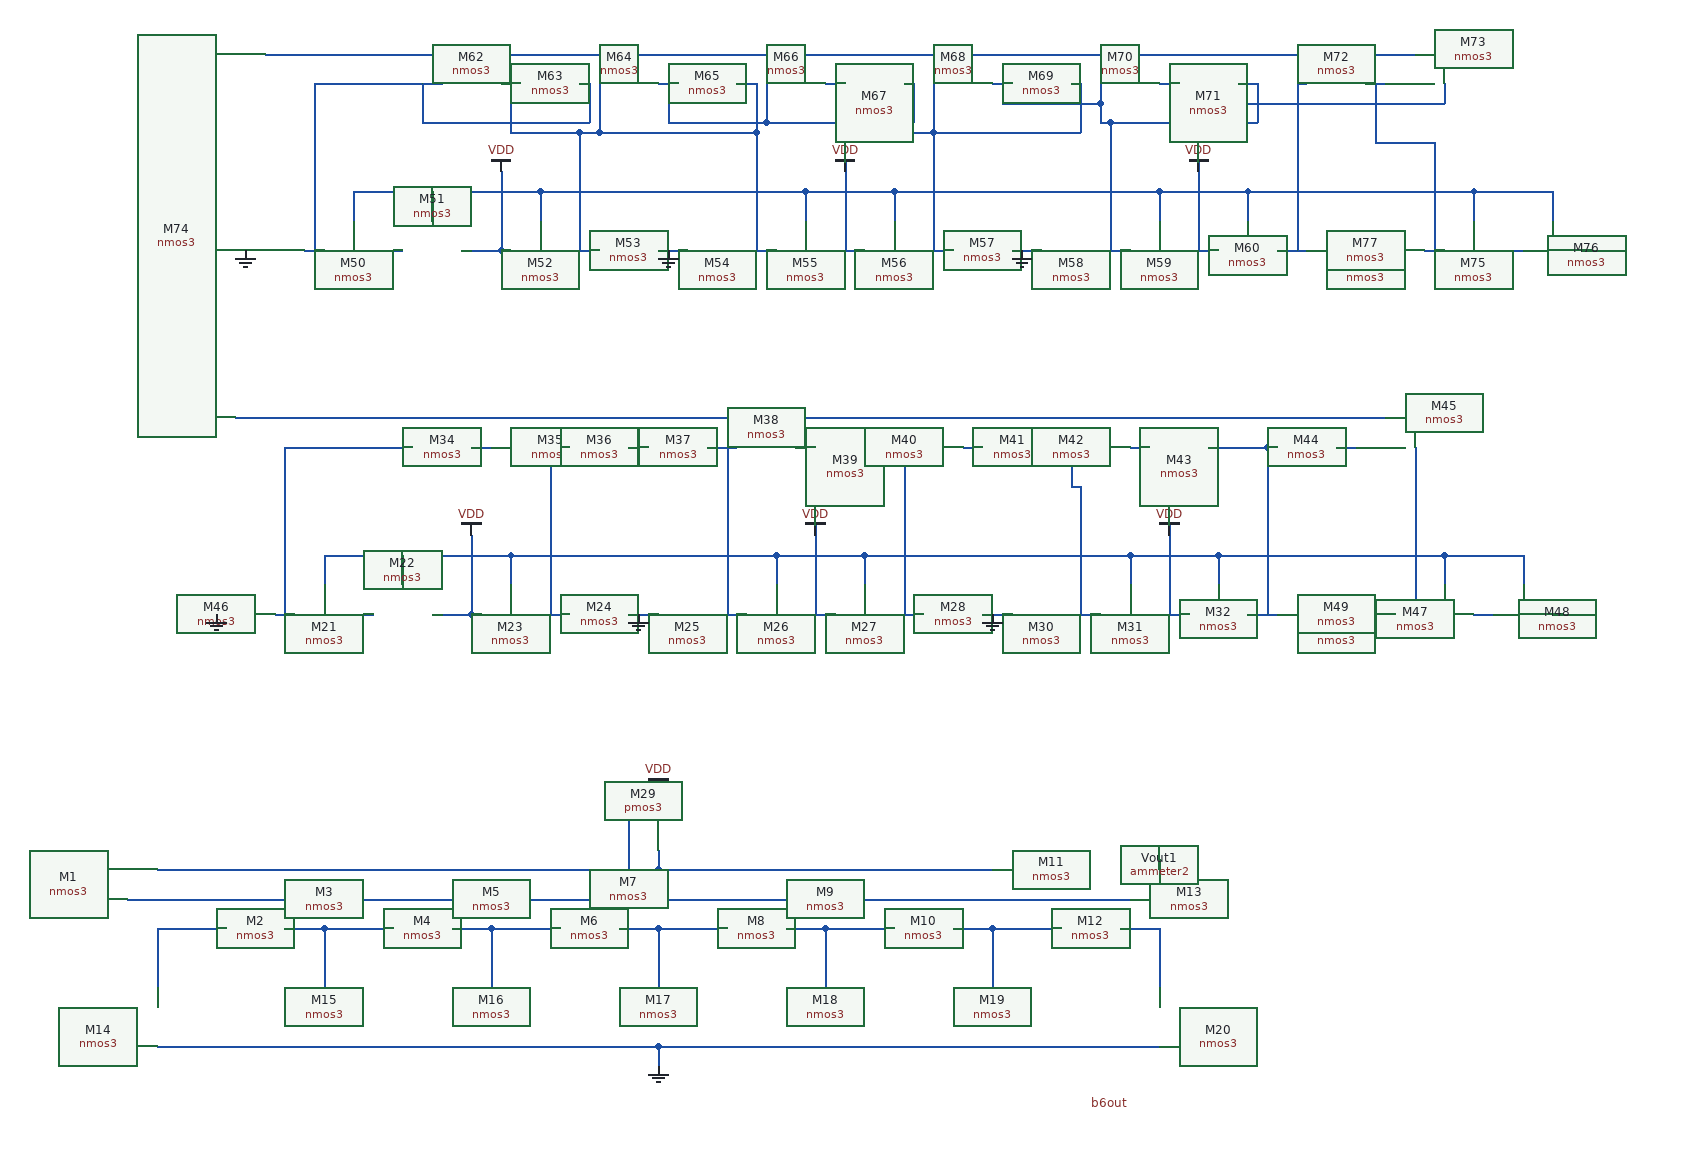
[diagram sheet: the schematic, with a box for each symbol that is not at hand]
v {xschem version=3.4.3 file_version=1.2
}
G {}
K {}
V {}
S {}
E {}
N -10 90 60 90 {
lab=#net1}
N -40 60 90 60 {
lab=#net2}
N 90 60 130 60 {
lab=#net2}
N 120 90 160 90 {
lab=#net3}
N 160 90 230 90 {
lab=#net3}
N 130 60 260 60 {
lab=#net2}
N 260 60 300 60 {
lab=#net2}
N 290 90 330 90 {
lab=#net4}
N 330 90 400 90 {
lab=#net4}
N 300 60 430 60 {
lab=#net2}
N 430 60 470 60 {
lab=#net2}
N 460 90 500 90 {
lab=#net5}
N 500 90 570 90 {
lab=#net5}
N 470 60 600 60 {
lab=#net2}
N 600 60 640 60 {
lab=#net2}
N 630 90 670 90 {
lab=#net6}
N 670 90 740 90 {
lab=#net6}
N 640 60 770 60 {
lab=#net2}
N 770 60 810 60 {
lab=#net2}
N 800 90 840 90 {
lab=#net7}
N 840 90 910 90 {
lab=#net7}
N 810 60 940 60 {
lab=#net2}
N 940 60 980 60 {
lab=#net2}
N 970 90 1010 90 {
lab=#net8}
N -10 90 -10 150 {
lab=#net1}
N 160 90 160 150 {
lab=#net3}
N 330 90 330 150 {
lab=#net4}
N 500 90 500 150 {
lab=#net5}
N 670 90 670 150 {
lab=#net6}
N 840 90 840 150 {
lab=#net7}
N 1010 90 1010 150 {
lab=#net8}
N -10 210 160 210 {
lab=GND}
N 160 210 330 210 {
lab=GND}
N 330 210 500 210 {
lab=GND}
N 500 210 670 210 {
lab=GND}
N 670 210 840 210 {
lab=GND}
N 840 210 1010 210 {
lab=GND}
N 500 210 500 230 {
lab=GND}
N -10 30 160 30 {
lab=#net9}
N 160 30 330 30 {
lab=#net9}
N 330 30 500 30 {
lab=#net9}
N 500 30 670 30 {
lab=#net9}
N 670 30 840 30 {
lab=#net9}
N 500 10 500 30 {
lab=#net9}
N 1010 20 1010 30 {
lab=#net10}
N 470 -20 470 30 {
lab=#net9}
N 190 -230 210 -230 {
lab=#net11}
N 270 -230 280 -230 {
lab=VDD}
N 380 -230 410 -230 {
lab=#net12}
N 560 -230 590 -230 {
lab=#net13}
N 740 -230 770 -230 {
lab=#net14}
N 920 -230 950 -230 {
lab=#net15}
N 1100 -230 1130 -230 {
lab=#net16}
N 470 -230 500 -230 {
lab=GND}
N 650 -230 680 -230 {
lab=VDD}
N 830 -230 860 -230 {
lab=GND}
N 1010 -230 1040 -230 {
lab=VDD}
N 310 -230 320 -230 {
lab=VDD}
N 310 -310 310 -230 {
lab=VDD}
N 350 -290 350 -260 {
lab=#net17}
N 350 -290 620 -290 {
lab=#net17}
N 620 -290 620 -260 {
lab=#net17}
N 660 -320 660 -230 {
lab=VDD}
N 750 -260 750 -230 {
lab=#net14}
N 570 -260 570 -230 {
lab=#net13}
N 390 -260 390 -230 {
lab=#net12}
N 930 -260 930 -230 {
lab=#net15}
N 1020 -320 1020 -230 {
lab=VDD}
N 620 -290 710 -290 {
lab=#net17}
N 710 -290 710 -270 {
lab=#net17}
N 710 -270 710 -260 {
lab=#net17}
N 710 -290 980 -290 {
lab=#net17}
N 980 -290 980 -260 {
lab=#net17}
N 1120 -260 1120 -230 {
lab=#net16}
N 980 -290 1070 -290 {
lab=#net17}
N 1070 -290 1070 -260 {
lab=#net17}
N 280 -430 360 -430 {
lab=#net18}
N 310 -400 330 -400 {
lab=#net19}
N 390 -400 400 -400 {
lab=#net12}
N 440 -430 520 -430 {
lab=#net20}
N 470 -400 490 -400 {
lab=#net21}
N 550 -400 560 -400 {
lab=#net13}
N 610 -430 690 -430 {
lab=#net22}
N 640 -400 660 -400 {
lab=#net23}
N 720 -400 730 -400 {
lab=#net24}
N 780 -430 860 -430 {
lab=#net25}
N 810 -400 830 -400 {
lab=#net26}
N 890 -400 900 -400 {
lab=#net15}
N 950 -430 1030 -430 {
lab=#net27}
N 980 -400 1000 -400 {
lab=#net28}
N 1060 -400 1070 -400 {
lab=#net16}
N 400 -400 410 -400 {
lab=#net12}
N 560 -400 580 -400 {
lab=#net13}
N 730 -400 750 -400 {
lab=#net24}
N 900 -400 920 -400 {
lab=#net15}
N 390 -400 390 -260 {
lab=#net12}
N 570 -400 570 -260 {
lab=#net13}
N 750 -400 750 -270 {
lab=#net24}
N 930 -360 930 -260 {
lab=#net15}
N 920 -360 930 -360 {
lab=#net15}
N 920 -400 920 -360 {
lab=#net15}
N 1120 -400 1120 -260 {
lab=#net16}
N 1070 -400 1120 -400 {
lab=#net16}
N 1160 -430 1240 -430 {
lab=#net29}
N 1190 -400 1210 -400 {
lab=#net30}
N 1120 -400 1130 -400 {
lab=#net16}
N 280 -230 310 -230 {
lab=VDD}
N 110 -230 130 -230 {
lab=#net32}
N 160 -290 350 -290 {
lab=#net17}
N 160 -290 160 -270 {
lab=#net17}
N 240 -290 240 -270 {
lab=#net17}
N 160 -270 160 -260 {
lab=#net17}
N 240 -270 240 -260 {
lab=#net17}
N 1330 -230 1350 -230 {
lab=#net33}
N 1410 -230 1420 -230 {
lab=#net34}
N 1250 -230 1270 -230 {
lab=#net35}
N 1300 -290 1300 -270 {
lab=#net36}
N 1380 -290 1380 -270 {
lab=#net37}
N 1300 -270 1300 -260 {
lab=#net36}
N 1380 -270 1380 -260 {
lab=#net37}
N 1300 -290 1380 -290 {}
N 1070 -290 1300 -290 {}
N 120 -400 120 -230 {}
N 120 -400 240 -400 {}
N 240 -400 250 -400 {}
N 1270 -400 1270 -230 {}
N 1030 -430 1160 -430 {}
N 860 -430 950 -430 {}
N 690 -430 780 -430 {}
N 520 -430 610 -430 {}
N 360 -430 440 -430 {}
N 70 -430 280 -430 {}
N 220 -600 240 -600 {
lab=#net11}
N 300 -600 310 -600 {
lab=VDD}
N 410 -600 440 -600 {
lab=#net12}
N 590 -600 620 -600 {
lab=#net13}
N 770 -600 800 -600 {
lab=#net14}
N 950 -600 980 -600 {
lab=#net15}
N 1130 -600 1160 -600 {
lab=#net16}
N 500 -600 530 -600 {
lab=GND}
N 680 -600 710 -600 {
lab=VDD}
N 860 -600 890 -600 {
lab=GND}
N 1040 -600 1070 -600 {
lab=VDD}
N 340 -600 350 -600 {
lab=VDD}
N 340 -680 340 -600 {
lab=VDD}
N 380 -660 380 -630 {
lab=#net17}
N 380 -660 650 -660 {
lab=#net17}
N 650 -660 650 -630 {
lab=#net17}
N 690 -690 690 -600 {
lab=VDD}
N 780 -630 780 -600 {
lab=#net14}
N 600 -630 600 -600 {
lab=#net13}
N 420 -630 420 -600 {
lab=#net12}
N 960 -630 960 -600 {
lab=#net15}
N 1050 -690 1050 -600 {
lab=VDD}
N 650 -660 740 -660 {
lab=#net17}
N 740 -660 740 -640 {
lab=#net17}
N 740 -640 740 -630 {
lab=#net17}
N 740 -660 1010 -660 {
lab=#net17}
N 1010 -660 1010 -630 {
lab=#net17}
N 1150 -630 1150 -600 {
lab=#net16}
N 1010 -660 1100 -660 {
lab=#net17}
N 1100 -660 1100 -630 {
lab=#net17}
N 310 -800 390 -800 {
lab=#net18}
N 340 -770 360 -770 {
lab=#net19}
N 420 -770 430 -770 {
lab=#net12}
N 470 -800 550 -800 {
lab=#net20}
N 500 -770 520 -770 {
lab=#net21}
N 580 -770 590 -770 {
lab=#net13}
N 640 -800 720 -800 {
lab=#net22}
N 670 -770 690 -770 {
lab=#net23}
N 750 -770 760 -770 {
lab=#net24}
N 810 -800 890 -800 {
lab=#net25}
N 840 -770 860 -770 {
lab=#net26}
N 920 -770 930 -770 {
lab=#net15}
N 980 -800 1060 -800 {
lab=#net27}
N 1010 -770 1030 -770 {
lab=#net28}
N 1090 -770 1100 -770 {
lab=#net16}
N 960 -730 960 -630 {
lab=#net15}
N 1150 -770 1150 -630 {
lab=#net16}
N 1190 -800 1270 -800 {
lab=#net29}
N 1220 -770 1240 -770 {
lab=#net30}
N 1150 -770 1160 -770 {
lab=#net16}
N 310 -600 340 -600 {
lab=VDD}
N 140 -600 160 -600 {
lab=#net32}
N 190 -660 380 -660 {
lab=#net17}
N 190 -660 190 -640 {
lab=#net17}
N 270 -660 270 -640 {
lab=#net17}
N 190 -640 190 -630 {
lab=#net17}
N 270 -640 270 -630 {
lab=#net17}
N 1360 -600 1380 -600 {
lab=#net33}
N 1440 -600 1450 -600 {
lab=#net34}
N 1280 -600 1300 -600 {
lab=#net35}
N 1330 -660 1330 -640 {
lab=#net36}
N 1410 -660 1410 -640 {
lab=#net37}
N 1330 -640 1330 -630 {
lab=#net36}
N 1410 -640 1410 -630 {
lab=#net37}
N 1330 -660 1410 -660 {}
N 1100 -660 1330 -660 {}
N 150 -770 150 -600 {}
N 150 -770 270 -770 {}
N 270 -770 280 -770 {}
N 1060 -800 1190 -800 {}
N 890 -800 980 -800 {}
N 720 -800 810 -800 {}
N 550 -800 640 -800 {}
N 390 -800 470 -800 {}
N 100 -800 310 -800 {}
N 420 -720 420 -630 {}
N 350 -720 420 -720 {}
N 350 -770 350 -720 {}
N 260 -770 260 -730 {}
N 260 -730 430 -730 {}
N 430 -770 430 -730 {}
N 420 -720 440 -720 {}
N 440 -770 440 -720 {}
N 600 -720 600 -630 {}
N 600 -770 600 -720 {}
N 590 -770 600 -770 {}
N 510 -770 510 -730 {}
N 510 -730 610 -730 {}
N 610 -770 610 -730 {}
N 440 -720 600 -720 {}
N 750 -270 750 -260 {}
N 780 -720 780 -630 {}
N 680 -720 780 -720 {}
N 680 -770 680 -720 {}
N 610 -730 760 -730 {}
N 760 -770 760 -730 {}
N 780 -770 780 -720 {}
N 780 -720 930 -720 {}
N 930 -770 930 -720 {}
N 850 -770 850 -750 {}
N 850 -750 950 -750 {}
N 950 -770 950 -750 {}
N 950 -750 950 -730 {}
N 950 -730 960 -730 {}
N 960 -730 1110 -730 {}
N 1110 -770 1110 -730 {}
N 1100 -770 1110 -770 {}
N 1020 -770 1020 -750 {}
N 1020 -750 1150 -750 {}
N 1150 -750 1300 -750 {}
N 1300 -770 1300 -750 {}
N 1290 -710 1290 -600 {}
N 1230 -710 1290 -710 {}
N 1230 -770 1230 -710 {}
C {madvlsi/nmos3.sym} -10 60 0 0 {name=M1
L=\{L\}
W=\{W\}
body=GND
nf=1
mult=2
ad="'int((nf+1)/2) * W/nf * 0.29'" 
pd="'2*int((nf+1)/2) * (W/nf + 0.29)'"
as="'int((nf+2)/2) * W/nf * 0.29'" 
ps="'2*int((nf+2)/2) * (W/nf + 0.29)'"
nrd="'0.29 / W'" nrs="'0.29 / W'"
sa=0 sb=0 sd=0
model=nfet_01v8
spiceprefix=X
}
C {madvlsi/nmos3.sym} 90 90 1 0 {name=M2
L=\{L\}
W=\{W\}
body=GND
nf=1
mult=2
ad="'int((nf+1)/2) * W/nf * 0.29'" 
pd="'2*int((nf+1)/2) * (W/nf + 0.29)'"
as="'int((nf+2)/2) * W/nf * 0.29'" 
ps="'2*int((nf+2)/2) * (W/nf + 0.29)'"
nrd="'0.29 / W'" nrs="'0.29 / W'"
sa=0 sb=0 sd=0
model=nfet_01v8
spiceprefix=X
}
C {madvlsi/nmos3.sym} 160 60 0 0 {name=M3
L=\{L\}
W=\{W\}
body=GND
nf=1
mult=1
ad="'int((nf+1)/2) * W/nf * 0.29'" 
pd="'2*int((nf+1)/2) * (W/nf + 0.29)'"
as="'int((nf+2)/2) * W/nf * 0.29'" 
ps="'2*int((nf+2)/2) * (W/nf + 0.29)'"
nrd="'0.29 / W'" nrs="'0.29 / W'"
sa=0 sb=0 sd=0
model=nfet_01v8
spiceprefix=X
}
C {madvlsi/nmos3.sym} 260 90 1 0 {name=M4
L=\{L\}
W=\{W\}
body=GND
nf=1
mult=2
ad="'int((nf+1)/2) * W/nf * 0.29'" 
pd="'2*int((nf+1)/2) * (W/nf + 0.29)'"
as="'int((nf+2)/2) * W/nf * 0.29'" 
ps="'2*int((nf+2)/2) * (W/nf + 0.29)'"
nrd="'0.29 / W'" nrs="'0.29 / W'"
sa=0 sb=0 sd=0
model=nfet_01v8
spiceprefix=X
}
C {madvlsi/nmos3.sym} 330 60 0 0 {name=M5
L=\{L\}
W=\{W\}
body=GND
nf=1
mult=1
ad="'int((nf+1)/2) * W/nf * 0.29'" 
pd="'2*int((nf+1)/2) * (W/nf + 0.29)'"
as="'int((nf+2)/2) * W/nf * 0.29'" 
ps="'2*int((nf+2)/2) * (W/nf + 0.29)'"
nrd="'0.29 / W'" nrs="'0.29 / W'"
sa=0 sb=0 sd=0
model=nfet_01v8
spiceprefix=X
}
C {madvlsi/nmos3.sym} 430 90 1 0 {name=M6
L=\{L\}
W=\{W\}
body=GND
nf=1
mult=2
ad="'int((nf+1)/2) * W/nf * 0.29'" 
pd="'2*int((nf+1)/2) * (W/nf + 0.29)'"
as="'int((nf+2)/2) * W/nf * 0.29'" 
ps="'2*int((nf+2)/2) * (W/nf + 0.29)'"
nrd="'0.29 / W'" nrs="'0.29 / W'"
sa=0 sb=0 sd=0
model=nfet_01v8
spiceprefix=X
}
C {madvlsi/nmos3.sym} 500 60 0 0 {name=M7
L=\{L\}
W=\{W\}
body=GND
nf=1
mult=1
ad="'int((nf+1)/2) * W/nf * 0.29'" 
pd="'2*int((nf+1)/2) * (W/nf + 0.29)'"
as="'int((nf+2)/2) * W/nf * 0.29'" 
ps="'2*int((nf+2)/2) * (W/nf + 0.29)'"
nrd="'0.29 / W'" nrs="'0.29 / W'"
sa=0 sb=0 sd=0
model=nfet_01v8
spiceprefix=X
}
C {madvlsi/nmos3.sym} 600 90 1 0 {name=M8
L=\{L\}
W=\{W\}
body=GND
nf=1
mult=2
ad="'int((nf+1)/2) * W/nf * 0.29'" 
pd="'2*int((nf+1)/2) * (W/nf + 0.29)'"
as="'int((nf+2)/2) * W/nf * 0.29'" 
ps="'2*int((nf+2)/2) * (W/nf + 0.29)'"
nrd="'0.29 / W'" nrs="'0.29 / W'"
sa=0 sb=0 sd=0
model=nfet_01v8
spiceprefix=X
}
C {madvlsi/nmos3.sym} 670 60 0 0 {name=M9
L=\{L\}
W=\{W\}
body=GND
nf=1
mult=1
ad="'int((nf+1)/2) * W/nf * 0.29'" 
pd="'2*int((nf+1)/2) * (W/nf + 0.29)'"
as="'int((nf+2)/2) * W/nf * 0.29'" 
ps="'2*int((nf+2)/2) * (W/nf + 0.29)'"
nrd="'0.29 / W'" nrs="'0.29 / W'"
sa=0 sb=0 sd=0
model=nfet_01v8
spiceprefix=X
}
C {madvlsi/nmos3.sym} 770 90 1 0 {name=M10
L=\{L\}
W=\{W\}
body=GND
nf=1
mult=2
ad="'int((nf+1)/2) * W/nf * 0.29'" 
pd="'2*int((nf+1)/2) * (W/nf + 0.29)'"
as="'int((nf+2)/2) * W/nf * 0.29'" 
ps="'2*int((nf+2)/2) * (W/nf + 0.29)'"
nrd="'0.29 / W'" nrs="'0.29 / W'"
sa=0 sb=0 sd=0
model=nfet_01v8
spiceprefix=X
}
C {madvlsi/nmos3.sym} 840 60 0 0 {name=M11
L=\{L\}
W=\{W\}
body=GND
nf=1
mult=1
ad="'int((nf+1)/2) * W/nf * 0.29'" 
pd="'2*int((nf+1)/2) * (W/nf + 0.29)'"
as="'int((nf+2)/2) * W/nf * 0.29'" 
ps="'2*int((nf+2)/2) * (W/nf + 0.29)'"
nrd="'0.29 / W'" nrs="'0.29 / W'"
sa=0 sb=0 sd=0
model=nfet_01v8
spiceprefix=X
}
C {madvlsi/nmos3.sym} 940 90 1 0 {name=M12
L=\{L\}
W=\{W\}
body=GND
nf=1
mult=2
ad="'int((nf+1)/2) * W/nf * 0.29'" 
pd="'2*int((nf+1)/2) * (W/nf + 0.29)'"
as="'int((nf+2)/2) * W/nf * 0.29'" 
ps="'2*int((nf+2)/2) * (W/nf + 0.29)'"
nrd="'0.29 / W'" nrs="'0.29 / W'"
sa=0 sb=0 sd=0
model=nfet_01v8
spiceprefix=X
}
C {madvlsi/nmos3.sym} 1010 60 0 0 {name=M13
L=\{L\}
W=\{W\}
body=GND
nf=1
mult=2
ad="'int((nf+1)/2) * W/nf * 0.29'" 
pd="'2*int((nf+1)/2) * (W/nf + 0.29)'"
as="'int((nf+2)/2) * W/nf * 0.29'" 
ps="'2*int((nf+2)/2) * (W/nf + 0.29)'"
nrd="'0.29 / W'" nrs="'0.29 / W'"
sa=0 sb=0 sd=0
model=nfet_01v8
spiceprefix=X
}
C {madvlsi/nmos3.sym} -10 180 0 0 {name=M14
L=\{L\}
W=\{W\}
body=GND
nf=1
mult=1
ad="'int((nf+1)/2) * W/nf * 0.29'" 
pd="'2*int((nf+1)/2) * (W/nf + 0.29)'"
as="'int((nf+2)/2) * W/nf * 0.29'" 
ps="'2*int((nf+2)/2) * (W/nf + 0.29)'"
nrd="'0.29 / W'" nrs="'0.29 / W'"
sa=0 sb=0 sd=0
model=nfet_01v8
spiceprefix=X
}
C {madvlsi/nmos3.sym} 160 180 0 0 {name=M15
L=\{L\}
W=\{W\}
body=GND
nf=1
mult=1
ad="'int((nf+1)/2) * W/nf * 0.29'" 
pd="'2*int((nf+1)/2) * (W/nf + 0.29)'"
as="'int((nf+2)/2) * W/nf * 0.29'" 
ps="'2*int((nf+2)/2) * (W/nf + 0.29)'"
nrd="'0.29 / W'" nrs="'0.29 / W'"
sa=0 sb=0 sd=0
model=nfet_01v8
spiceprefix=X
}
C {madvlsi/nmos3.sym} 330 180 0 0 {name=M16
L=\{L\}
W=\{W\}
body=GND
nf=1
mult=1
ad="'int((nf+1)/2) * W/nf * 0.29'" 
pd="'2*int((nf+1)/2) * (W/nf + 0.29)'"
as="'int((nf+2)/2) * W/nf * 0.29'" 
ps="'2*int((nf+2)/2) * (W/nf + 0.29)'"
nrd="'0.29 / W'" nrs="'0.29 / W'"
sa=0 sb=0 sd=0
model=nfet_01v8
spiceprefix=X
}
C {madvlsi/nmos3.sym} 500 180 0 0 {name=M17
L=\{L\}
W=\{W\}
body=GND
nf=1
mult=1
ad="'int((nf+1)/2) * W/nf * 0.29'" 
pd="'2*int((nf+1)/2) * (W/nf + 0.29)'"
as="'int((nf+2)/2) * W/nf * 0.29'" 
ps="'2*int((nf+2)/2) * (W/nf + 0.29)'"
nrd="'0.29 / W'" nrs="'0.29 / W'"
sa=0 sb=0 sd=0
model=nfet_01v8
spiceprefix=X
}
C {madvlsi/nmos3.sym} 670 180 0 0 {name=M18
L=\{L\}
W=\{W\}
body=GND
nf=1
mult=1
ad="'int((nf+1)/2) * W/nf * 0.29'" 
pd="'2*int((nf+1)/2) * (W/nf + 0.29)'"
as="'int((nf+2)/2) * W/nf * 0.29'" 
ps="'2*int((nf+2)/2) * (W/nf + 0.29)'"
nrd="'0.29 / W'" nrs="'0.29 / W'"
sa=0 sb=0 sd=0
model=nfet_01v8
spiceprefix=X
}
C {madvlsi/nmos3.sym} 840 180 0 0 {name=M19
L=\{L\}
W=\{W\}
body=GND
nf=1
mult=1
ad="'int((nf+1)/2) * W/nf * 0.29'" 
pd="'2*int((nf+1)/2) * (W/nf + 0.29)'"
as="'int((nf+2)/2) * W/nf * 0.29'" 
ps="'2*int((nf+2)/2) * (W/nf + 0.29)'"
nrd="'0.29 / W'" nrs="'0.29 / W'"
sa=0 sb=0 sd=0
model=nfet_01v8
spiceprefix=X
}
C {madvlsi/nmos3.sym} 1010 180 0 0 {name=M20
L=\{L\}
W=\{W\}
body=GND
nf=1
mult=1
ad="'int((nf+1)/2) * W/nf * 0.29'" 
pd="'2*int((nf+1)/2) * (W/nf + 0.29)'"
as="'int((nf+2)/2) * W/nf * 0.29'" 
ps="'2*int((nf+2)/2) * (W/nf + 0.29)'"
nrd="'0.29 / W'" nrs="'0.29 / W'"
sa=0 sb=0 sd=0
model=nfet_01v8
spiceprefix=X
}
C {madvlsi/gnd.sym} 500 230 0 0 {name=l1 lab=GND}
C {madvlsi/vdd.sym} 500 -50 0 0 {name=l2 lab=VDD}
C {madvlsi/pmos3.sym} 500 -20 0 0 {name=M29
L=\{L\}
W=\{W\}
body=VDD
nf=1
mult=1
ad="'int((nf+1)/2) * W/nf * 0.29'" 
pd="'2*int((nf+1)/2) * (W/nf + 0.29)'"
as="'int((nf+2)/2) * W/nf * 0.29'" 
ps="'2*int((nf+2)/2) * (W/nf + 0.29)'"
nrd="'0.29 / W'" nrs="'0.29 / W'"
sa=0 sb=0 sd=0
model=pfet_01v8
spiceprefix=X
}
C {devices/lab_pin.sym} 980 270 0 0 {name=p26 sig_type=std_logic lab=b6out
}
C {madvlsi/ammeter2.sym} 1010 10 0 0 {name=Vout1}
C {madvlsi/nmos3.sym} 160 -230 1 0 {name=M21
L=\{L\}
W=\{W\}
body=GND
nf=1
mult=1
ad="'int((nf+1)/2) * W/nf * 0.29'" 
pd="'2*int((nf+1)/2) * (W/nf + 0.29)'"
as="'int((nf+2)/2) * W/nf * 0.29'" 
ps="'2*int((nf+2)/2) * (W/nf + 0.29)'"
nrd="'0.29 / W'" nrs="'0.29 / W'"
sa=0 sb=0 sd=0
model=nfet_01v8
spiceprefix=X
}
C {madvlsi/nmos3.sym} 240 -230 1 0 {name=M22
L=\{L\}
W=\{W\}
body=GND
nf=1
mult=1
ad="'int((nf+1)/2) * W/nf * 0.29'" 
pd="'2*int((nf+1)/2) * (W/nf + 0.29)'"
as="'int((nf+2)/2) * W/nf * 0.29'" 
ps="'2*int((nf+2)/2) * (W/nf + 0.29)'"
nrd="'0.29 / W'" nrs="'0.29 / W'"
sa=0 sb=0 sd=0
model=nfet_01v8
spiceprefix=X
}
C {madvlsi/nmos3.sym} 350 -230 1 0 {name=M23
L=\{L\}
W=\{W\}
body=GND
nf=1
mult=1
ad="'int((nf+1)/2) * W/nf * 0.29'" 
pd="'2*int((nf+1)/2) * (W/nf + 0.29)'"
as="'int((nf+2)/2) * W/nf * 0.29'" 
ps="'2*int((nf+2)/2) * (W/nf + 0.29)'"
nrd="'0.29 / W'" nrs="'0.29 / W'"
sa=0 sb=0 sd=0
model=nfet_01v8
spiceprefix=X
}
C {madvlsi/nmos3.sym} 440 -230 1 0 {name=M24
L=\{L\}
W=\{W\}
body=GND
nf=1
mult=1
ad="'int((nf+1)/2) * W/nf * 0.29'" 
pd="'2*int((nf+1)/2) * (W/nf + 0.29)'"
as="'int((nf+2)/2) * W/nf * 0.29'" 
ps="'2*int((nf+2)/2) * (W/nf + 0.29)'"
nrd="'0.29 / W'" nrs="'0.29 / W'"
sa=0 sb=0 sd=0
model=nfet_01v8
spiceprefix=X
}
C {madvlsi/nmos3.sym} 530 -230 1 0 {name=M25
L=\{L\}
W=\{W\}
body=GND
nf=1
mult=1
ad="'int((nf+1)/2) * W/nf * 0.29'" 
pd="'2*int((nf+1)/2) * (W/nf + 0.29)'"
as="'int((nf+2)/2) * W/nf * 0.29'" 
ps="'2*int((nf+2)/2) * (W/nf + 0.29)'"
nrd="'0.29 / W'" nrs="'0.29 / W'"
sa=0 sb=0 sd=0
model=nfet_01v8
spiceprefix=X
}
C {madvlsi/nmos3.sym} 620 -230 1 0 {name=M26
L=\{L\}
W=\{W\}
body=GND
nf=1
mult=1
ad="'int((nf+1)/2) * W/nf * 0.29'" 
pd="'2*int((nf+1)/2) * (W/nf + 0.29)'"
as="'int((nf+2)/2) * W/nf * 0.29'" 
ps="'2*int((nf+2)/2) * (W/nf + 0.29)'"
nrd="'0.29 / W'" nrs="'0.29 / W'"
sa=0 sb=0 sd=0
model=nfet_01v8
spiceprefix=X
}
C {madvlsi/nmos3.sym} 710 -230 1 0 {name=M27
L=\{L\}
W=\{W\}
body=GND
nf=1
mult=1
ad="'int((nf+1)/2) * W/nf * 0.29'" 
pd="'2*int((nf+1)/2) * (W/nf + 0.29)'"
as="'int((nf+2)/2) * W/nf * 0.29'" 
ps="'2*int((nf+2)/2) * (W/nf + 0.29)'"
nrd="'0.29 / W'" nrs="'0.29 / W'"
sa=0 sb=0 sd=0
model=nfet_01v8
spiceprefix=X
}
C {madvlsi/nmos3.sym} 800 -230 1 0 {name=M28
L=\{L\}
W=\{W\}
body=GND
nf=1
mult=1
ad="'int((nf+1)/2) * W/nf * 0.29'" 
pd="'2*int((nf+1)/2) * (W/nf + 0.29)'"
as="'int((nf+2)/2) * W/nf * 0.29'" 
ps="'2*int((nf+2)/2) * (W/nf + 0.29)'"
nrd="'0.29 / W'" nrs="'0.29 / W'"
sa=0 sb=0 sd=0
model=nfet_01v8
spiceprefix=X
}
C {madvlsi/nmos3.sym} 890 -230 1 0 {name=M30
L=\{L\}
W=\{W\}
body=GND
nf=1
mult=1
ad="'int((nf+1)/2) * W/nf * 0.29'" 
pd="'2*int((nf+1)/2) * (W/nf + 0.29)'"
as="'int((nf+2)/2) * W/nf * 0.29'" 
ps="'2*int((nf+2)/2) * (W/nf + 0.29)'"
nrd="'0.29 / W'" nrs="'0.29 / W'"
sa=0 sb=0 sd=0
model=nfet_01v8
spiceprefix=X
}
C {madvlsi/nmos3.sym} 980 -230 1 0 {name=M31
L=\{L\}
W=\{W\}
body=GND
nf=1
mult=1
ad="'int((nf+1)/2) * W/nf * 0.29'" 
pd="'2*int((nf+1)/2) * (W/nf + 0.29)'"
as="'int((nf+2)/2) * W/nf * 0.29'" 
ps="'2*int((nf+2)/2) * (W/nf + 0.29)'"
nrd="'0.29 / W'" nrs="'0.29 / W'"
sa=0 sb=0 sd=0
model=nfet_01v8
spiceprefix=X
}
C {madvlsi/nmos3.sym} 1070 -230 1 0 {name=M32
L=\{L\}
W=\{W\}
body=GND
nf=1
mult=1
ad="'int((nf+1)/2) * W/nf * 0.29'" 
pd="'2*int((nf+1)/2) * (W/nf + 0.29)'"
as="'int((nf+2)/2) * W/nf * 0.29'" 
ps="'2*int((nf+2)/2) * (W/nf + 0.29)'"
nrd="'0.29 / W'" nrs="'0.29 / W'"
sa=0 sb=0 sd=0
model=nfet_01v8
spiceprefix=X
}
C {madvlsi/nmos3.sym} 1160 -230 1 0 {name=M33
L=\{L\}
W=\{W\}
body=GND
nf=1
mult=1
ad="'int((nf+1)/2) * W/nf * 0.29'" 
pd="'2*int((nf+1)/2) * (W/nf + 0.29)'"
as="'int((nf+2)/2) * W/nf * 0.29'" 
ps="'2*int((nf+2)/2) * (W/nf + 0.29)'"
nrd="'0.29 / W'" nrs="'0.29 / W'"
sa=0 sb=0 sd=0
model=nfet_01v8
spiceprefix=X
}
C {madvlsi/gnd.sym} 480 -230 0 0 {name=l3 lab=GND}
C {madvlsi/gnd.sym} 840 -230 0 0 {name=l4 lab=GND}
C {madvlsi/vdd.sym} 310 -310 0 0 {name=l5 lab=VDD}
C {madvlsi/vdd.sym} 660 -310 0 0 {name=l6 lab=VDD}
C {madvlsi/vdd.sym} 1020 -310 0 0 {name=l7 lab=VDD}
C {madvlsi/gnd.sym} 1190 -230 0 0 {name=l8 lab=GND}
C {madvlsi/nmos3.sym} 280 -400 1 0 {name=M34
L=\{L\}
W=\{W\}
body=GND
nf=1
mult=1
ad="'int((nf+1)/2) * W/nf * 0.29'" 
pd="'2*int((nf+1)/2) * (W/nf + 0.29)'"
as="'int((nf+2)/2) * W/nf * 0.29'" 
ps="'2*int((nf+2)/2) * (W/nf + 0.29)'"
nrd="'0.29 / W'" nrs="'0.29 / W'"
sa=0 sb=0 sd=0
model=nfet_01v8
spiceprefix=X
}
C {madvlsi/nmos3.sym} 360 -400 1 0 {name=M35
L=\{L\}
W=\{W\}
body=GND
nf=1
mult=1
ad="'int((nf+1)/2) * W/nf * 0.29'" 
pd="'2*int((nf+1)/2) * (W/nf + 0.29)'"
as="'int((nf+2)/2) * W/nf * 0.29'" 
ps="'2*int((nf+2)/2) * (W/nf + 0.29)'"
nrd="'0.29 / W'" nrs="'0.29 / W'"
sa=0 sb=0 sd=0
model=nfet_01v8
spiceprefix=X
}
C {madvlsi/nmos3.sym} 440 -400 1 0 {name=M36
L=\{L\}
W=\{W\}
body=GND
nf=1
mult=1
ad="'int((nf+1)/2) * W/nf * 0.29'" 
pd="'2*int((nf+1)/2) * (W/nf + 0.29)'"
as="'int((nf+2)/2) * W/nf * 0.29'" 
ps="'2*int((nf+2)/2) * (W/nf + 0.29)'"
nrd="'0.29 / W'" nrs="'0.29 / W'"
sa=0 sb=0 sd=0
model=nfet_01v8
spiceprefix=X
}
C {madvlsi/nmos3.sym} 520 -400 1 0 {name=M37
L=\{L\}
W=\{W\}
body=GND
nf=1
mult=1
ad="'int((nf+1)/2) * W/nf * 0.29'" 
pd="'2*int((nf+1)/2) * (W/nf + 0.29)'"
as="'int((nf+2)/2) * W/nf * 0.29'" 
ps="'2*int((nf+2)/2) * (W/nf + 0.29)'"
nrd="'0.29 / W'" nrs="'0.29 / W'"
sa=0 sb=0 sd=0
model=nfet_01v8
spiceprefix=X
}
C {madvlsi/nmos3.sym} 610 -400 1 0 {name=M38
L=\{L\}
W=\{W\}
body=GND
nf=1
mult=1
ad="'int((nf+1)/2) * W/nf * 0.29'" 
pd="'2*int((nf+1)/2) * (W/nf + 0.29)'"
as="'int((nf+2)/2) * W/nf * 0.29'" 
ps="'2*int((nf+2)/2) * (W/nf + 0.29)'"
nrd="'0.29 / W'" nrs="'0.29 / W'"
sa=0 sb=0 sd=0
model=nfet_01v8
spiceprefix=X
}
C {madvlsi/nmos3.sym} 690 -400 1 0 {name=M39
L=\{L\}
W=\{W\}
body=GND
nf=1
mult=1
ad="'int((nf+1)/2) * W/nf * 0.29'" 
pd="'2*int((nf+1)/2) * (W/nf + 0.29)'"
as="'int((nf+2)/2) * W/nf * 0.29'" 
ps="'2*int((nf+2)/2) * (W/nf + 0.29)'"
nrd="'0.29 / W'" nrs="'0.29 / W'"
sa=0 sb=0 sd=0
model=nfet_01v8
spiceprefix=X
}
C {madvlsi/nmos3.sym} 780 -400 1 0 {name=M40
L=\{L\}
W=\{W\}
body=GND
nf=1
mult=1
ad="'int((nf+1)/2) * W/nf * 0.29'" 
pd="'2*int((nf+1)/2) * (W/nf + 0.29)'"
as="'int((nf+2)/2) * W/nf * 0.29'" 
ps="'2*int((nf+2)/2) * (W/nf + 0.29)'"
nrd="'0.29 / W'" nrs="'0.29 / W'"
sa=0 sb=0 sd=0
model=nfet_01v8
spiceprefix=X
}
C {madvlsi/nmos3.sym} 860 -400 1 0 {name=M41
L=\{L\}
W=\{W\}
body=GND
nf=1
mult=1
ad="'int((nf+1)/2) * W/nf * 0.29'" 
pd="'2*int((nf+1)/2) * (W/nf + 0.29)'"
as="'int((nf+2)/2) * W/nf * 0.29'" 
ps="'2*int((nf+2)/2) * (W/nf + 0.29)'"
nrd="'0.29 / W'" nrs="'0.29 / W'"
sa=0 sb=0 sd=0
model=nfet_01v8
spiceprefix=X
}
C {madvlsi/nmos3.sym} 950 -400 1 0 {name=M42
L=\{L\}
W=\{W\}
body=GND
nf=1
mult=1
ad="'int((nf+1)/2) * W/nf * 0.29'" 
pd="'2*int((nf+1)/2) * (W/nf + 0.29)'"
as="'int((nf+2)/2) * W/nf * 0.29'" 
ps="'2*int((nf+2)/2) * (W/nf + 0.29)'"
nrd="'0.29 / W'" nrs="'0.29 / W'"
sa=0 sb=0 sd=0
model=nfet_01v8
spiceprefix=X
}
C {madvlsi/nmos3.sym} 1030 -400 1 0 {name=M43
L=\{L\}
W=\{W\}
body=GND
nf=1
mult=1
ad="'int((nf+1)/2) * W/nf * 0.29'" 
pd="'2*int((nf+1)/2) * (W/nf + 0.29)'"
as="'int((nf+2)/2) * W/nf * 0.29'" 
ps="'2*int((nf+2)/2) * (W/nf + 0.29)'"
nrd="'0.29 / W'" nrs="'0.29 / W'"
sa=0 sb=0 sd=0
model=nfet_01v8
spiceprefix=X
}
C {madvlsi/nmos3.sym} 1160 -400 1 0 {name=M44
L=\{L\}
W=\{W\}
body=GND
nf=1
mult=1
ad="'int((nf+1)/2) * W/nf * 0.29'" 
pd="'2*int((nf+1)/2) * (W/nf + 0.29)'"
as="'int((nf+2)/2) * W/nf * 0.29'" 
ps="'2*int((nf+2)/2) * (W/nf + 0.29)'"
nrd="'0.29 / W'" nrs="'0.29 / W'"
sa=0 sb=0 sd=0
model=nfet_01v8
spiceprefix=X
}
C {madvlsi/nmos3.sym} 1240 -400 1 0 {name=M45
L=\{L\}
W=\{W\}
body=GND
nf=1
mult=1
ad="'int((nf+1)/2) * W/nf * 0.29'" 
pd="'2*int((nf+1)/2) * (W/nf + 0.29)'"
as="'int((nf+2)/2) * W/nf * 0.29'" 
ps="'2*int((nf+2)/2) * (W/nf + 0.29)'"
nrd="'0.29 / W'" nrs="'0.29 / W'"
sa=0 sb=0 sd=0
model=nfet_01v8
spiceprefix=X
}
C {madvlsi/nmos3.sym} 80 -230 1 0 {name=M46
L=\{L\}
W=\{W\}
body=GND
nf=1
mult=1
ad="'int((nf+1)/2) * W/nf * 0.29'" 
pd="'2*int((nf+1)/2) * (W/nf + 0.29)'"
as="'int((nf+2)/2) * W/nf * 0.29'" 
ps="'2*int((nf+2)/2) * (W/nf + 0.29)'"
nrd="'0.29 / W'" nrs="'0.29 / W'"
sa=0 sb=0 sd=0
model=nfet_01v8
spiceprefix=X
}
C {madvlsi/gnd.sym} 50 -230 0 0 {name=l9 lab=GND}
C {madvlsi/nmos3.sym} 1300 -230 1 0 {name=M47
L=\{L\}
W=\{W\}
body=GND
nf=1
mult=1
ad="'int((nf+1)/2) * W/nf * 0.29'" 
pd="'2*int((nf+1)/2) * (W/nf + 0.29)'"
as="'int((nf+2)/2) * W/nf * 0.29'" 
ps="'2*int((nf+2)/2) * (W/nf + 0.29)'"
nrd="'0.29 / W'" nrs="'0.29 / W'"
sa=0 sb=0 sd=0
model=nfet_01v8
spiceprefix=X
}
C {madvlsi/nmos3.sym} 1380 -230 1 0 {name=M48
L=\{L\}
W=\{W\}
body=GND
nf=1
mult=1
ad="'int((nf+1)/2) * W/nf * 0.29'" 
pd="'2*int((nf+1)/2) * (W/nf + 0.29)'"
as="'int((nf+2)/2) * W/nf * 0.29'" 
ps="'2*int((nf+2)/2) * (W/nf + 0.29)'"
nrd="'0.29 / W'" nrs="'0.29 / W'"
sa=0 sb=0 sd=0
model=nfet_01v8
spiceprefix=X
}
C {madvlsi/nmos3.sym} 1220 -230 1 0 {name=M49
L=\{L\}
W=\{W\}
body=GND
nf=1
mult=1
ad="'int((nf+1)/2) * W/nf * 0.29'" 
pd="'2*int((nf+1)/2) * (W/nf + 0.29)'"
as="'int((nf+2)/2) * W/nf * 0.29'" 
ps="'2*int((nf+2)/2) * (W/nf + 0.29)'"
nrd="'0.29 / W'" nrs="'0.29 / W'"
sa=0 sb=0 sd=0
model=nfet_01v8
spiceprefix=X
}
C {madvlsi/nmos3.sym} 190 -600 1 0 {name=M50
L=\{L\}
W=\{W\}
body=GND
nf=1
mult=1
ad="'int((nf+1)/2) * W/nf * 0.29'" 
pd="'2*int((nf+1)/2) * (W/nf + 0.29)'"
as="'int((nf+2)/2) * W/nf * 0.29'" 
ps="'2*int((nf+2)/2) * (W/nf + 0.29)'"
nrd="'0.29 / W'" nrs="'0.29 / W'"
sa=0 sb=0 sd=0
model=nfet_01v8
spiceprefix=X
}
C {madvlsi/nmos3.sym} 270 -600 1 0 {name=M51
L=\{L\}
W=\{W\}
body=GND
nf=1
mult=1
ad="'int((nf+1)/2) * W/nf * 0.29'" 
pd="'2*int((nf+1)/2) * (W/nf + 0.29)'"
as="'int((nf+2)/2) * W/nf * 0.29'" 
ps="'2*int((nf+2)/2) * (W/nf + 0.29)'"
nrd="'0.29 / W'" nrs="'0.29 / W'"
sa=0 sb=0 sd=0
model=nfet_01v8
spiceprefix=X
}
C {madvlsi/nmos3.sym} 380 -600 1 0 {name=M52
L=\{L\}
W=\{W\}
body=GND
nf=1
mult=1
ad="'int((nf+1)/2) * W/nf * 0.29'" 
pd="'2*int((nf+1)/2) * (W/nf + 0.29)'"
as="'int((nf+2)/2) * W/nf * 0.29'" 
ps="'2*int((nf+2)/2) * (W/nf + 0.29)'"
nrd="'0.29 / W'" nrs="'0.29 / W'"
sa=0 sb=0 sd=0
model=nfet_01v8
spiceprefix=X
}
C {madvlsi/nmos3.sym} 470 -600 1 0 {name=M53
L=\{L\}
W=\{W\}
body=GND
nf=1
mult=1
ad="'int((nf+1)/2) * W/nf * 0.29'" 
pd="'2*int((nf+1)/2) * (W/nf + 0.29)'"
as="'int((nf+2)/2) * W/nf * 0.29'" 
ps="'2*int((nf+2)/2) * (W/nf + 0.29)'"
nrd="'0.29 / W'" nrs="'0.29 / W'"
sa=0 sb=0 sd=0
model=nfet_01v8
spiceprefix=X
}
C {madvlsi/nmos3.sym} 560 -600 1 0 {name=M54
L=\{L\}
W=\{W\}
body=GND
nf=1
mult=1
ad="'int((nf+1)/2) * W/nf * 0.29'" 
pd="'2*int((nf+1)/2) * (W/nf + 0.29)'"
as="'int((nf+2)/2) * W/nf * 0.29'" 
ps="'2*int((nf+2)/2) * (W/nf + 0.29)'"
nrd="'0.29 / W'" nrs="'0.29 / W'"
sa=0 sb=0 sd=0
model=nfet_01v8
spiceprefix=X
}
C {madvlsi/nmos3.sym} 650 -600 1 0 {name=M55
L=\{L\}
W=\{W\}
body=GND
nf=1
mult=1
ad="'int((nf+1)/2) * W/nf * 0.29'" 
pd="'2*int((nf+1)/2) * (W/nf + 0.29)'"
as="'int((nf+2)/2) * W/nf * 0.29'" 
ps="'2*int((nf+2)/2) * (W/nf + 0.29)'"
nrd="'0.29 / W'" nrs="'0.29 / W'"
sa=0 sb=0 sd=0
model=nfet_01v8
spiceprefix=X
}
C {madvlsi/nmos3.sym} 740 -600 1 0 {name=M56
L=\{L\}
W=\{W\}
body=GND
nf=1
mult=1
ad="'int((nf+1)/2) * W/nf * 0.29'" 
pd="'2*int((nf+1)/2) * (W/nf + 0.29)'"
as="'int((nf+2)/2) * W/nf * 0.29'" 
ps="'2*int((nf+2)/2) * (W/nf + 0.29)'"
nrd="'0.29 / W'" nrs="'0.29 / W'"
sa=0 sb=0 sd=0
model=nfet_01v8
spiceprefix=X
}
C {madvlsi/nmos3.sym} 830 -600 1 0 {name=M57
L=\{L\}
W=\{W\}
body=GND
nf=1
mult=1
ad="'int((nf+1)/2) * W/nf * 0.29'" 
pd="'2*int((nf+1)/2) * (W/nf + 0.29)'"
as="'int((nf+2)/2) * W/nf * 0.29'" 
ps="'2*int((nf+2)/2) * (W/nf + 0.29)'"
nrd="'0.29 / W'" nrs="'0.29 / W'"
sa=0 sb=0 sd=0
model=nfet_01v8
spiceprefix=X
}
C {madvlsi/nmos3.sym} 920 -600 1 0 {name=M58
L=\{L\}
W=\{W\}
body=GND
nf=1
mult=1
ad="'int((nf+1)/2) * W/nf * 0.29'" 
pd="'2*int((nf+1)/2) * (W/nf + 0.29)'"
as="'int((nf+2)/2) * W/nf * 0.29'" 
ps="'2*int((nf+2)/2) * (W/nf + 0.29)'"
nrd="'0.29 / W'" nrs="'0.29 / W'"
sa=0 sb=0 sd=0
model=nfet_01v8
spiceprefix=X
}
C {madvlsi/nmos3.sym} 1010 -600 1 0 {name=M59
L=\{L\}
W=\{W\}
body=GND
nf=1
mult=1
ad="'int((nf+1)/2) * W/nf * 0.29'" 
pd="'2*int((nf+1)/2) * (W/nf + 0.29)'"
as="'int((nf+2)/2) * W/nf * 0.29'" 
ps="'2*int((nf+2)/2) * (W/nf + 0.29)'"
nrd="'0.29 / W'" nrs="'0.29 / W'"
sa=0 sb=0 sd=0
model=nfet_01v8
spiceprefix=X
}
C {madvlsi/nmos3.sym} 1100 -600 1 0 {name=M60
L=\{L\}
W=\{W\}
body=GND
nf=1
mult=1
ad="'int((nf+1)/2) * W/nf * 0.29'" 
pd="'2*int((nf+1)/2) * (W/nf + 0.29)'"
as="'int((nf+2)/2) * W/nf * 0.29'" 
ps="'2*int((nf+2)/2) * (W/nf + 0.29)'"
nrd="'0.29 / W'" nrs="'0.29 / W'"
sa=0 sb=0 sd=0
model=nfet_01v8
spiceprefix=X
}
C {madvlsi/nmos3.sym} 1190 -600 1 0 {name=M61
L=\{L\}
W=\{W\}
body=GND
nf=1
mult=1
ad="'int((nf+1)/2) * W/nf * 0.29'" 
pd="'2*int((nf+1)/2) * (W/nf + 0.29)'"
as="'int((nf+2)/2) * W/nf * 0.29'" 
ps="'2*int((nf+2)/2) * (W/nf + 0.29)'"
nrd="'0.29 / W'" nrs="'0.29 / W'"
sa=0 sb=0 sd=0
model=nfet_01v8
spiceprefix=X
}
C {madvlsi/gnd.sym} 510 -600 0 0 {name=l10 lab=GND}
C {madvlsi/gnd.sym} 870 -600 0 0 {name=l11 lab=GND}
C {madvlsi/vdd.sym} 340 -680 0 0 {name=l12 lab=VDD}
C {madvlsi/vdd.sym} 690 -680 0 0 {name=l13 lab=VDD}
C {madvlsi/vdd.sym} 1050 -680 0 0 {name=l14 lab=VDD}
C {madvlsi/gnd.sym} 1220 -600 0 0 {name=l15 lab=GND}
C {madvlsi/nmos3.sym} 310 -770 1 0 {name=M62
L=\{L\}
W=\{W\}
body=GND
nf=1
mult=1
ad="'int((nf+1)/2) * W/nf * 0.29'" 
pd="'2*int((nf+1)/2) * (W/nf + 0.29)'"
as="'int((nf+2)/2) * W/nf * 0.29'" 
ps="'2*int((nf+2)/2) * (W/nf + 0.29)'"
nrd="'0.29 / W'" nrs="'0.29 / W'"
sa=0 sb=0 sd=0
model=nfet_01v8
spiceprefix=X
}
C {madvlsi/nmos3.sym} 390 -770 1 0 {name=M63
L=\{L\}
W=\{W\}
body=GND
nf=1
mult=1
ad="'int((nf+1)/2) * W/nf * 0.29'" 
pd="'2*int((nf+1)/2) * (W/nf + 0.29)'"
as="'int((nf+2)/2) * W/nf * 0.29'" 
ps="'2*int((nf+2)/2) * (W/nf + 0.29)'"
nrd="'0.29 / W'" nrs="'0.29 / W'"
sa=0 sb=0 sd=0
model=nfet_01v8
spiceprefix=X
}
C {madvlsi/nmos3.sym} 470 -770 1 0 {name=M64
L=\{L\}
W=\{W\}
body=GND
nf=1
mult=1
ad="'int((nf+1)/2) * W/nf * 0.29'" 
pd="'2*int((nf+1)/2) * (W/nf + 0.29)'"
as="'int((nf+2)/2) * W/nf * 0.29'" 
ps="'2*int((nf+2)/2) * (W/nf + 0.29)'"
nrd="'0.29 / W'" nrs="'0.29 / W'"
sa=0 sb=0 sd=0
model=nfet_01v8
spiceprefix=X
}
C {madvlsi/nmos3.sym} 550 -770 1 0 {name=M65
L=\{L\}
W=\{W\}
body=GND
nf=1
mult=1
ad="'int((nf+1)/2) * W/nf * 0.29'" 
pd="'2*int((nf+1)/2) * (W/nf + 0.29)'"
as="'int((nf+2)/2) * W/nf * 0.29'" 
ps="'2*int((nf+2)/2) * (W/nf + 0.29)'"
nrd="'0.29 / W'" nrs="'0.29 / W'"
sa=0 sb=0 sd=0
model=nfet_01v8
spiceprefix=X
}
C {madvlsi/nmos3.sym} 640 -770 1 0 {name=M66
L=\{L\}
W=\{W\}
body=GND
nf=1
mult=1
ad="'int((nf+1)/2) * W/nf * 0.29'" 
pd="'2*int((nf+1)/2) * (W/nf + 0.29)'"
as="'int((nf+2)/2) * W/nf * 0.29'" 
ps="'2*int((nf+2)/2) * (W/nf + 0.29)'"
nrd="'0.29 / W'" nrs="'0.29 / W'"
sa=0 sb=0 sd=0
model=nfet_01v8
spiceprefix=X
}
C {madvlsi/nmos3.sym} 720 -770 1 0 {name=M67
L=\{L\}
W=\{W\}
body=GND
nf=1
mult=1
ad="'int((nf+1)/2) * W/nf * 0.29'" 
pd="'2*int((nf+1)/2) * (W/nf + 0.29)'"
as="'int((nf+2)/2) * W/nf * 0.29'" 
ps="'2*int((nf+2)/2) * (W/nf + 0.29)'"
nrd="'0.29 / W'" nrs="'0.29 / W'"
sa=0 sb=0 sd=0
model=nfet_01v8
spiceprefix=X
}
C {madvlsi/nmos3.sym} 810 -770 1 0 {name=M68
L=\{L\}
W=\{W\}
body=GND
nf=1
mult=1
ad="'int((nf+1)/2) * W/nf * 0.29'" 
pd="'2*int((nf+1)/2) * (W/nf + 0.29)'"
as="'int((nf+2)/2) * W/nf * 0.29'" 
ps="'2*int((nf+2)/2) * (W/nf + 0.29)'"
nrd="'0.29 / W'" nrs="'0.29 / W'"
sa=0 sb=0 sd=0
model=nfet_01v8
spiceprefix=X
}
C {madvlsi/nmos3.sym} 890 -770 1 0 {name=M69
L=\{L\}
W=\{W\}
body=GND
nf=1
mult=1
ad="'int((nf+1)/2) * W/nf * 0.29'" 
pd="'2*int((nf+1)/2) * (W/nf + 0.29)'"
as="'int((nf+2)/2) * W/nf * 0.29'" 
ps="'2*int((nf+2)/2) * (W/nf + 0.29)'"
nrd="'0.29 / W'" nrs="'0.29 / W'"
sa=0 sb=0 sd=0
model=nfet_01v8
spiceprefix=X
}
C {madvlsi/nmos3.sym} 980 -770 1 0 {name=M70
L=\{L\}
W=\{W\}
body=GND
nf=1
mult=1
ad="'int((nf+1)/2) * W/nf * 0.29'" 
pd="'2*int((nf+1)/2) * (W/nf + 0.29)'"
as="'int((nf+2)/2) * W/nf * 0.29'" 
ps="'2*int((nf+2)/2) * (W/nf + 0.29)'"
nrd="'0.29 / W'" nrs="'0.29 / W'"
sa=0 sb=0 sd=0
model=nfet_01v8
spiceprefix=X
}
C {madvlsi/nmos3.sym} 1060 -770 1 0 {name=M71
L=\{L\}
W=\{W\}
body=GND
nf=1
mult=1
ad="'int((nf+1)/2) * W/nf * 0.29'" 
pd="'2*int((nf+1)/2) * (W/nf + 0.29)'"
as="'int((nf+2)/2) * W/nf * 0.29'" 
ps="'2*int((nf+2)/2) * (W/nf + 0.29)'"
nrd="'0.29 / W'" nrs="'0.29 / W'"
sa=0 sb=0 sd=0
model=nfet_01v8
spiceprefix=X
}
C {madvlsi/nmos3.sym} 1190 -770 1 0 {name=M72
L=\{L\}
W=\{W\}
body=GND
nf=1
mult=1
ad="'int((nf+1)/2) * W/nf * 0.29'" 
pd="'2*int((nf+1)/2) * (W/nf + 0.29)'"
as="'int((nf+2)/2) * W/nf * 0.29'" 
ps="'2*int((nf+2)/2) * (W/nf + 0.29)'"
nrd="'0.29 / W'" nrs="'0.29 / W'"
sa=0 sb=0 sd=0
model=nfet_01v8
spiceprefix=X
}
C {madvlsi/nmos3.sym} 1270 -770 1 0 {name=M73
L=\{L\}
W=\{W\}
body=GND
nf=1
mult=1
ad="'int((nf+1)/2) * W/nf * 0.29'" 
pd="'2*int((nf+1)/2) * (W/nf + 0.29)'"
as="'int((nf+2)/2) * W/nf * 0.29'" 
ps="'2*int((nf+2)/2) * (W/nf + 0.29)'"
nrd="'0.29 / W'" nrs="'0.29 / W'"
sa=0 sb=0 sd=0
model=nfet_01v8
spiceprefix=X
}
C {madvlsi/nmos3.sym} 110 -600 1 0 {name=M74
L=\{L\}
W=\{W\}
body=GND
nf=1
mult=1
ad="'int((nf+1)/2) * W/nf * 0.29'" 
pd="'2*int((nf+1)/2) * (W/nf + 0.29)'"
as="'int((nf+2)/2) * W/nf * 0.29'" 
ps="'2*int((nf+2)/2) * (W/nf + 0.29)'"
nrd="'0.29 / W'" nrs="'0.29 / W'"
sa=0 sb=0 sd=0
model=nfet_01v8
spiceprefix=X
}
C {madvlsi/gnd.sym} 80 -600 0 0 {name=l16 lab=GND}
C {madvlsi/nmos3.sym} 1330 -600 1 0 {name=M75
L=\{L\}
W=\{W\}
body=GND
nf=1
mult=1
ad="'int((nf+1)/2) * W/nf * 0.29'" 
pd="'2*int((nf+1)/2) * (W/nf + 0.29)'"
as="'int((nf+2)/2) * W/nf * 0.29'" 
ps="'2*int((nf+2)/2) * (W/nf + 0.29)'"
nrd="'0.29 / W'" nrs="'0.29 / W'"
sa=0 sb=0 sd=0
model=nfet_01v8
spiceprefix=X
}
C {madvlsi/nmos3.sym} 1410 -600 1 0 {name=M76
L=\{L\}
W=\{W\}
body=GND
nf=1
mult=1
ad="'int((nf+1)/2) * W/nf * 0.29'" 
pd="'2*int((nf+1)/2) * (W/nf + 0.29)'"
as="'int((nf+2)/2) * W/nf * 0.29'" 
ps="'2*int((nf+2)/2) * (W/nf + 0.29)'"
nrd="'0.29 / W'" nrs="'0.29 / W'"
sa=0 sb=0 sd=0
model=nfet_01v8
spiceprefix=X
}
C {madvlsi/nmos3.sym} 1250 -600 1 0 {name=M77
L=\{L\}
W=\{W\}
body=GND
nf=1
mult=1
ad="'int((nf+1)/2) * W/nf * 0.29'" 
pd="'2*int((nf+1)/2) * (W/nf + 0.29)'"
as="'int((nf+2)/2) * W/nf * 0.29'" 
ps="'2*int((nf+2)/2) * (W/nf + 0.29)'"
nrd="'0.29 / W'" nrs="'0.29 / W'"
sa=0 sb=0 sd=0
model=nfet_01v8
spiceprefix=X
}
